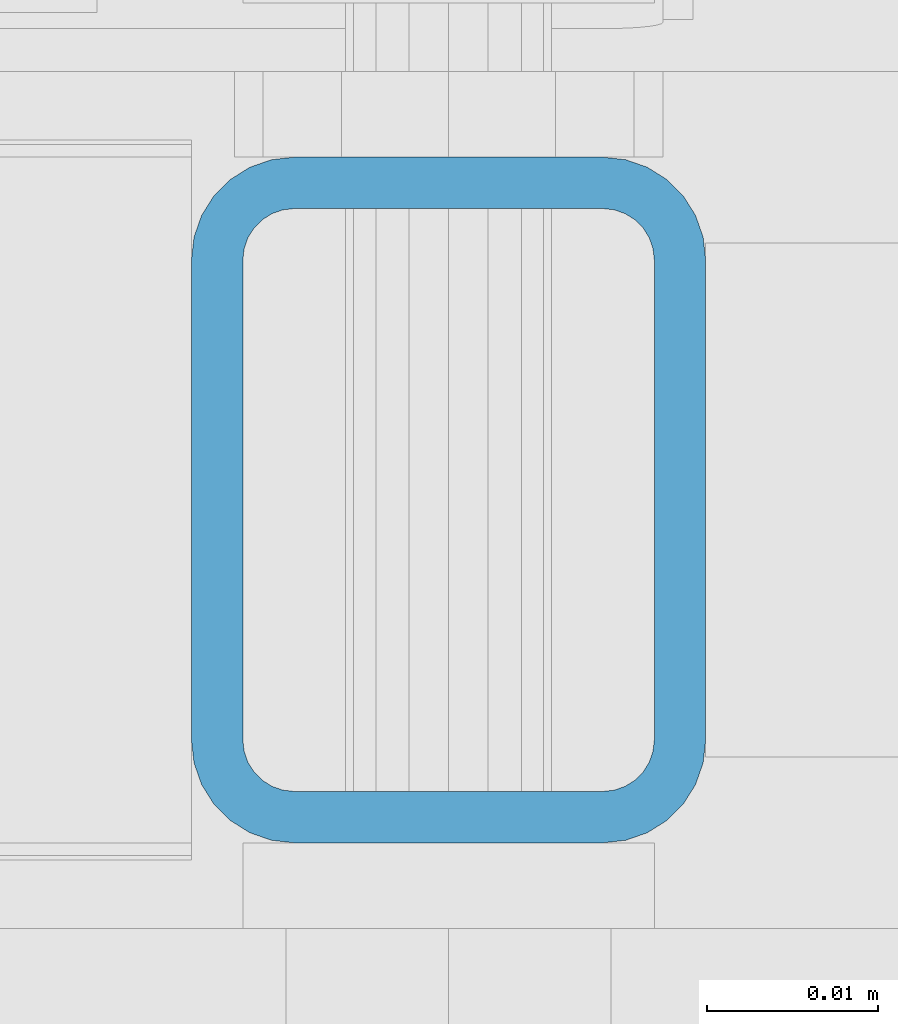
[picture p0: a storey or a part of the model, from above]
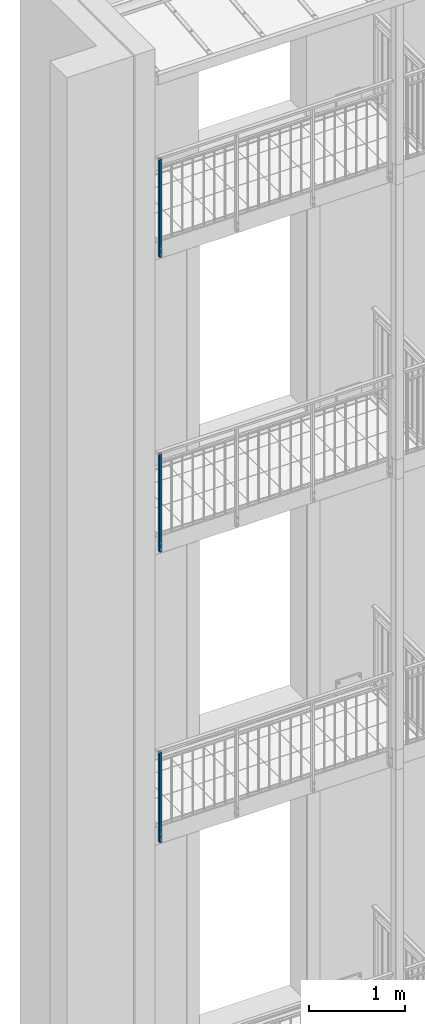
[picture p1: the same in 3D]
Properties of the parts of a building model (IFC2X3)

# File
Description: ViewDefinition[CoordinationView_V2.0]
File name: Modell J?ttemann_Hermannstr.1a, Frankfurt_ifc2x3.ifc
Time: 2026-07-18T19:59:10
Organization: J?ttemann, Schlo?str. 94, 60486 Frankfurt
Written by: IFC Toolkit 2.0.26.0
Made in: Advance Steel 2024

# IfcBuildingStorey, Default Storey
In: Struktur 1
Elevation: 0 mm

# IfcBeam: - (161)
In: Default Storey
Name | Description = Section | Material | Reference | Span (mm) | Slope (deg) | IsExternal = LoadBearing | SectionFamily
4 x - | R50X30X3 | S235JR | nicht definiert | 324.999 | 0 | no | RHS_Sections_rectang_c nach DIN
4 x - | R30X20X2 | S235JR | nicht definiert | 274.999 | 0 | no | RHS_Sections_rectang_c nach DIN
4 x - | R30X20X2 | S235JR | nicht definiert | 294.997 | 0 | no | RHS_Sections_rectang_c nach DIN
8 x - | R30X20X2 | S235JR | nicht definiert | 94.9986 | 0 | no | RHS_Sections_rectang_c nach DIN
16 x - | RHS80X60X4 | S235JR | nicht definiert | 1119 | 0 | no | RHS_Sections_rectang_c nach DIN
20 x - | RHS80X60X4 | S235JR | nicht definiert | 1092 | 0 | no | RHS_Sections_rectang_c nach DIN
36 x - |  | Alu | nicht definiert | 960 | 0 | no
8 x - | G 230x4 (Typ II) | S355JR | nicht definiert | 3262 | 0 | no | Usr G-Profile Typ II
8 x - | G 230x4 (Typ II) | S355JR | nicht definiert | 1122 | 0 | no | Usr G-Profile Typ II
4 x - | R50X30X3 | S235JR | nicht definiert | 1180 | 0 | no | RHS_Sections_rectang_c nach DIN
24 x - | R30X20X2 | S235JR | nicht definiert | 890 | 0 | no | RHS_Sections_rectang_c nach DIN
4 x - | R50X30X3 | S235JR | nicht definiert | 2830 | 0 | no | RHS_Sections_rectang_c nach DIN
8 x - | R30X20X2 | S235JR | nicht definiert | 990 | 0 | no | RHS_Sections_rectang_c nach DIN
12 x - | RO82.5x5 (Mannesmann) | S235JR | nicht definiert | 200 | 0 | no | Pipe nach mannesmann
- | Rinnenprofil 130x5 | S355JR |  |  |  |  | Usr Rinnenprofile

# IfcBeam: Column
In: Default Storey
Material: C20/25
Pset_BeamCommon - Reference: nicht definiert; Span: 4170 mm; Slope: 0 deg; IsExternal: no; LoadBearing: no

# IfcBeam: Gel?nder
In: Default Storey
Description: Q100X4; Material: S235JR
Pset_BeamCommon - Span: 3270 mm; Slope: 0 deg; IsExternal: no; LoadBearing: no
ProfileProperties - SectionFamily: RHS_Sections_square_c nach DIN; Section: Q100X4

# IfcBuildingElementProxy: - (508)
In: Default Storey
Name | Material
140 x  | Kein
18 x  | S235JR
130 x  | Kunststoff
40 x  | Alu
180 x  | A4

# IfcColumn: - (154)
In: Default Storey
Pset_ColumnCommon - Reference: nicht definiert; Slope: 0 deg; IsExternal: no; LoadBearing: no
Name | Description = Section | Material | SectionFamily
108 x - | RD12 | S235JR | Round nach DIN
4 x - | R30X20X2 | S235JR | RHS_Sections_rectang_c nach DIN
4 x - |  | S235JR
9 x - | Q100X4 | S235JR | RHS_Sections_square_c nach DIN
24 x - | R40X30X3 | S235JR | RHS_Sections_rectang_c nach DIN
5 x - | RO50x2.5 | A500 GR.C | RUS_R8732-78

# IfcMechanicalFastener: - (61)
In: Default Storey
Name | NominalDiameter (mm) | NominalLength (mm)
24 x  | 12 | 70
24 x  | 6 | 40
 | 8 | 20
8 x  | 12 | 60
4 x  | 12 | 35

# IfcMember: - (6)
In: Default Storey
Material: S235JR
ProfileProperties - SectionFamily: RHS_Sections_square_c nach DIN
Name | Description = Section
2 x - | Q100X4
4 x - | Q60X3

# IfcMember: Girder (14)
In: Default Storey
Pset_MemberCommon - Slope: 0 deg; IsExternal: no; LoadBearing: no
Name | Description = Section | Material | Span (mm) | SectionFamily
2 x Girder | FL20X8 | Alu | 1165 | Flat nach DIN
6 x Girder | Weichgummistreifen f?r Dachbelag 50x3 | Gummi | 1115 | Usr Dachprofile
6 x Girder | Abdeckleiste f?r Dachbelag 50x5 | Alu | 1165 | Usr Dachprofile

# IfcPlate: - (161)
In: Default Storey
Description: -
Pset_PlateCommon - IsExternal: no; LoadBearing: no
Name | Material | Reference
96 x - | BWS 40 mm | nicht definiert
15 x - | Thermostop 6 mm | nicht definiert
9 x - | S235JR 10 mm | nicht definiert
28 x - | S235JR 20 mm | nicht definiert
4 x - | S235JR 5 mm | nicht definiert
5 x - | Glas 8.76 mm
4 x - | S235JR 5 mm

# IfcSlab: - (15)
In: Default Storey
Description: -
Pset_SlabCommon - Reference: nicht definiert; IsExternal: no; LoadBearing: no; Combustible: no; Compartmentation: no; PitchAngle: 0 deg
Name | Material
4 x - | C25/30 20 mm
5 x - | C25/30 50 mm
- | C25/30 750 mm
- | C25/30 550 mm
- | C25/30 350 mm
- | C25/30 150 mm
- | C25/30 200 mm
- | C25/30 4170 mm

# IfcWall: - (5)
In: Default Storey
Description: -
Pset_WallCommon - Reference: nicht definiert; Combustible: no; IsExternal: no; ExtendToStructure: no; LoadBearing: no; Compartmentation: no
Name | Material
- | C25/30 800 mm
- | C25/30 240 mm
- | C25/30 700 mm
- | C25/30 500 mm
- | C25/30 5000 mm
